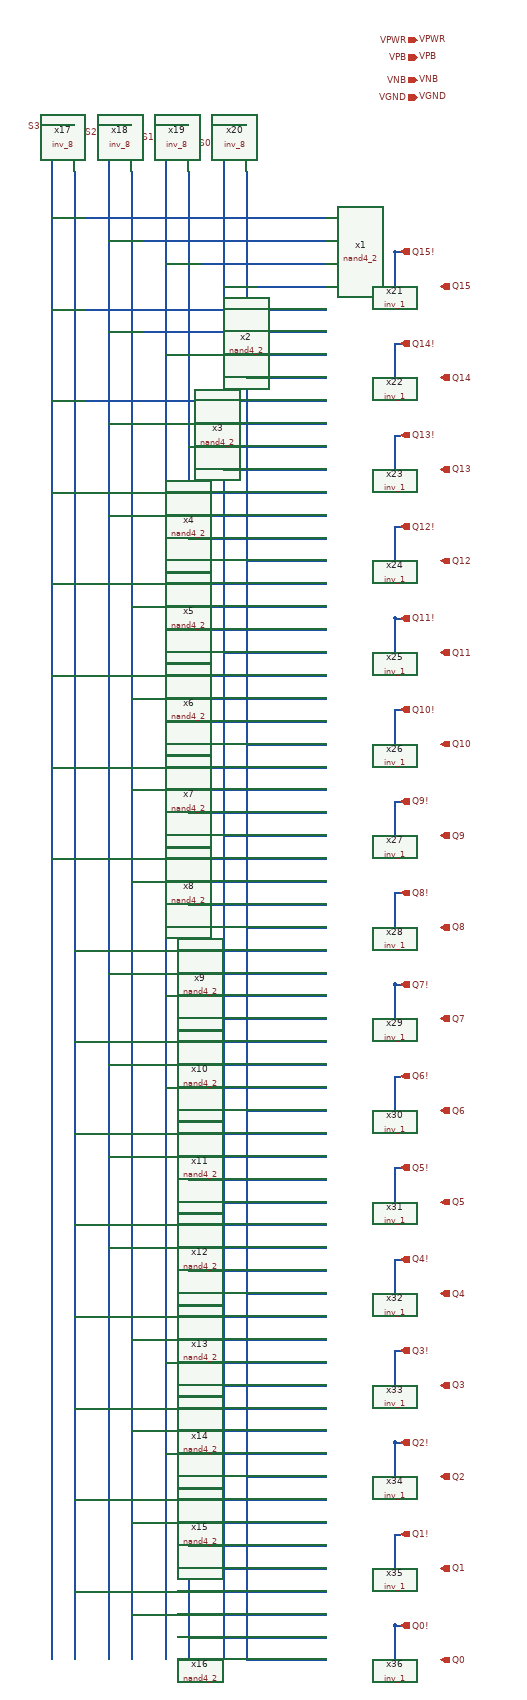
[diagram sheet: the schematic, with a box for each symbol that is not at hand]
v {xschem version=3.1.0 file_version=1.2
}
G {}
K {}
V {}
S {}
E {}
N 700 -2800 740 -2800 {
lab=S0}
N 700 -2800 700 -120 {
lab=S0}
N 600 -2800 600 -120 {
lab=S1}
N 500 -2800 500 -120 {
lab=S2}
N 400 -2800 400 -120 {
lab=S3}
N 600 -2800 640 -2800 {
lab=S1}
N 500 -2800 540 -2800 {
lab=S2}
N 400 -2800 440 -2800 {
lab=S3}
N 740 -2720 740 -120 {
lab=#net1}
N 640 -2720 640 -120 {
lab=#net2}
N 540 -2720 540 -120 {
lab=#net3}
N 440 -2720 440 -120 {
lab=#net4}
N 400 -2640 880 -2640 {
lab=S3}
N 500 -2600 880 -2600 {
lab=S2}
N 600 -2560 880 -2560 {
lab=S1}
N 700 -2520 880 -2520 {
lab=S0}
N 400 -2480 880 -2480 {
lab=S3}
N 400 -2320 880 -2320 {
lab=S3}
N 400 -2160 880 -2160 {
lab=S3}
N 400 -2000 880 -2000 {
lab=S3}
N 400 -1840 880 -1840 {
lab=S3}
N 400 -1680 880 -1680 {
lab=S3}
N 400 -1520 880 -1520 {
lab=S3}
N 500 -2440 880 -2440 {
lab=S2}
N 500 -2280 880 -2280 {
lab=S2}
N 500 -2120 880 -2120 {
lab=S2}
N 540 -1960 880 -1960 {
lab=#net3}
N 540 -1800 880 -1800 {
lab=#net3}
N 540 -1640 880 -1640 {
lab=#net3}
N 540 -1480 880 -1480 {
lab=#net3}
N 440 -1360 880 -1360 {
lab=#net4}
N 440 -1200 880 -1200 {
lab=#net4}
N 440 -1040 880 -1040 {
lab=#net4}
N 440 -880 880 -880 {
lab=#net4}
N 440 -720 880 -720 {
lab=#net4}
N 440 -560 880 -560 {
lab=#net4}
N 440 -400 880 -400 {
lab=#net4}
N 440 -240 880 -240 {
lab=#net4}
N 500 -1320 880 -1320 {
lab=S2}
N 500 -1160 880 -1160 {
lab=S2}
N 500 -1000 880 -1000 {
lab=S2}
N 500 -840 880 -840 {
lab=S2}
N 540 -680 880 -680 {
lab=#net3}
N 540 -520 880 -520 {
lab=#net3}
N 540 -360 880 -360 {
lab=#net3}
N 540 -200 880 -200 {
lab=#net3}
N 740 -2360 880 -2360 {
lab=#net1}
N 700 -2200 880 -2200 {
lab=S0}
N 740 -2040 880 -2040 {
lab=#net1}
N 700 -1880 880 -1880 {
lab=S0}
N 740 -1720 880 -1720 {
lab=#net1}
N 700 -1560 880 -1560 {
lab=S0}
N 740 -1400 880 -1400 {
lab=#net1}
N 700 -1240 880 -1240 {
lab=S0}
N 740 -1080 880 -1080 {
lab=#net1}
N 700 -920 880 -920 {
lab=S0}
N 740 -760 880 -760 {
lab=#net1}
N 700 -600 880 -600 {
lab=S0}
N 740 -440 880 -440 {
lab=#net1}
N 700 -280 880 -280 {
lab=S0}
N 740 -120 880 -120 {
lab=#net1}
N 600 -2400 880 -2400 {
lab=S1}
N 640 -2240 880 -2240 {
lab=#net2}
N 640 -2080 880 -2080 {
lab=#net2}
N 600 -1920 880 -1920 {
lab=S1}
N 600 -1760 880 -1760 {
lab=S1}
N 640 -1600 880 -1600 {
lab=#net2}
N 640 -1440 880 -1440 {
lab=#net2}
N 600 -1120 880 -1120 {
lab=S1}
N 640 -800 880 -800 {
lab=#net2}
N 600 -480 880 -480 {
lab=S1}
N 600 -1280 880 -1280 {
lab=S1}
N 640 -960 880 -960 {
lab=#net2}
N 600 -640 880 -640 {
lab=S1}
N 640 -320 880 -320 {
lab=#net2}
N 640 -160 880 -160 {
lab=#net2}
N 1000 -2580 1010 -2580 {
lab=Q15!}
N 1000 -2420 1010 -2420 {
lab=Q14!}
N 1000 -2580 1010 -2580 {
lab=Q15!}
N 1000 -2260 1010 -2260 {
lab=Q13!}
N 1000 -2100 1010 -2100 {
lab=Q12!}
N 1000 -1940 1010 -1940 {
lab=Q11!}
N 1000 -1780 1010 -1780 {
lab=Q10!}
N 1000 -1940 1010 -1940 {
lab=Q11!}
N 1000 -1620 1010 -1620 {
lab=Q9!}
N 1000 -1460 1010 -1460 {
lab=Q8!}
N 1000 -1300 1010 -1300 {
lab=Q7!}
N 1000 -1140 1010 -1140 {
lab=Q6!}
N 1000 -1300 1010 -1300 {
lab=Q7!}
N 1000 -820 1010 -820 {
lab=Q4!}
N 1000 -660 1010 -660 {
lab=Q3!}
N 1000 -500 1010 -500 {
lab=Q2!}
N 1000 -340 1010 -340 {
lab=Q1!}
N 1000 -500 1010 -500 {
lab=Q2!}
N 1000 -180 1010 -180 {
lab=Q0!}
N 1000 -180 1010 -180 {
lab=Q0!}
N 1000 -980 1010 -980 {
lab=Q5!}
N 1000 -2580 1000 -2520 {
lab=Q15!}
N 1000 -2420 1000 -2360 {
lab=Q14!}
N 1000 -2260 1000 -2200 {
lab=Q13!}
N 1000 -2100 1000 -2040 {
lab=Q12!}
N 1000 -1940 1000 -1880 {
lab=Q11!}
N 1000 -1780 1000 -1720 {
lab=Q10!}
N 1000 -1620 1000 -1560 {
lab=Q9!}
N 1000 -1460 1000 -1400 {
lab=Q8!}
N 1000 -1300 1000 -1240 {
lab=Q7!}
N 1000 -1140 1000 -1080 {
lab=Q6!}
N 1000 -980 1000 -920 {
lab=Q5!}
N 1000 -820 1000 -760 {
lab=Q4!}
N 1000 -660 1000 -600 {
lab=Q3!}
N 1000 -500 1000 -440 {
lab=Q2!}
N 1000 -340 1000 -280 {
lab=Q1!}
N 1000 -180 1000 -120 {
lab=Q0!}
C {devices/ipin.sym} 400 -2800 0 0 {name=p9 lab=S3}
C {devices/ipin.sym} 500 -2790 0 0 {name=p10 lab=S2}
C {devices/ipin.sym} 600 -2780 0 0 {name=p35 lab=S1}
C {devices/ipin.sym} 700 -2770 0 0 {name=p36 lab=S0}
C {devices/ipin.sym} 1040 -2850 0 0 {name=p37 lab=VGND}
C {devices/ipin.sym} 1040 -2950 0 0 {name=p38 lab=VPWR
}
C {devices/ipin.sym} 1040 -2880 0 0 {name=p41 lab=VNB}
C {devices/ipin.sym} 1040 -2920 0 0 {name=p42 lab=VPB

}
C {devices/lab_pin.sym} 1040 -2950 0 1 {name=p39 sig_type=std_logic lab=VPWR
}
C {devices/lab_pin.sym} 1040 -2850 0 1 {name=p40 sig_type=std_logic lab=VGND}
C {devices/lab_pin.sym} 1040 -2920 0 1 {name=p43 sig_type=std_logic lab=VPB}
C {devices/lab_pin.sym} 1040 -2880 0 1 {name=p44 sig_type=std_logic lab=VNB}
C {sky130_stdcells/nand4_2.sym} 940 -2580 0 0 {name=x1 VGND=VGND VNB=VNB VPB=VPB VPWR=VPWR prefix=sky130_fd_sc_hd__ }
C {sky130_stdcells/nand4_2.sym} 940 -2420 0 0 {name=x2 VGND=VGND VNB=VNB VPB=VPB VPWR=VPWR prefix=sky130_fd_sc_hd__ }
C {sky130_stdcells/nand4_2.sym} 940 -2260 0 0 {name=x3 VGND=VGND VNB=VNB VPB=VPB VPWR=VPWR prefix=sky130_fd_sc_hd__ }
C {sky130_stdcells/nand4_2.sym} 940 -2100 0 0 {name=x4 VGND=VGND VNB=VNB VPB=VPB VPWR=VPWR prefix=sky130_fd_sc_hd__ }
C {sky130_stdcells/nand4_2.sym} 940 -1940 0 0 {name=x5 VGND=VGND VNB=VNB VPB=VPB VPWR=VPWR prefix=sky130_fd_sc_hd__ }
C {sky130_stdcells/nand4_2.sym} 940 -1780 0 0 {name=x6 VGND=VGND VNB=VNB VPB=VPB VPWR=VPWR prefix=sky130_fd_sc_hd__ }
C {sky130_stdcells/nand4_2.sym} 940 -1620 0 0 {name=x7 VGND=VGND VNB=VNB VPB=VPB VPWR=VPWR prefix=sky130_fd_sc_hd__ }
C {sky130_stdcells/nand4_2.sym} 940 -1460 0 0 {name=x8 VGND=VGND VNB=VNB VPB=VPB VPWR=VPWR prefix=sky130_fd_sc_hd__ }
C {sky130_stdcells/nand4_2.sym} 940 -1300 0 0 {name=x9 VGND=VGND VNB=VNB VPB=VPB VPWR=VPWR prefix=sky130_fd_sc_hd__ }
C {sky130_stdcells/nand4_2.sym} 940 -1140 0 0 {name=x10 VGND=VGND VNB=VNB VPB=VPB VPWR=VPWR prefix=sky130_fd_sc_hd__ }
C {sky130_stdcells/nand4_2.sym} 940 -980 0 0 {name=x11 VGND=VGND VNB=VNB VPB=VPB VPWR=VPWR prefix=sky130_fd_sc_hd__ }
C {sky130_stdcells/nand4_2.sym} 940 -820 0 0 {name=x12 VGND=VGND VNB=VNB VPB=VPB VPWR=VPWR prefix=sky130_fd_sc_hd__ }
C {sky130_stdcells/nand4_2.sym} 940 -660 0 0 {name=x13 VGND=VGND VNB=VNB VPB=VPB VPWR=VPWR prefix=sky130_fd_sc_hd__ }
C {sky130_stdcells/nand4_2.sym} 940 -500 0 0 {name=x14 VGND=VGND VNB=VNB VPB=VPB VPWR=VPWR prefix=sky130_fd_sc_hd__ }
C {sky130_stdcells/nand4_2.sym} 940 -340 0 0 {name=x15 VGND=VGND VNB=VNB VPB=VPB VPWR=VPWR prefix=sky130_fd_sc_hd__ }
C {sky130_stdcells/nand4_2.sym} 940 -180 0 0 {name=x16 VGND=VGND VNB=VNB VPB=VPB VPWR=VPWR prefix=sky130_fd_sc_hd__ }
C {devices/opin.sym} 1010 -2420 0 0 {name=p1 lab=Q14!
}
C {devices/opin.sym} 1010 -2580 0 0 {name=p3 lab=Q15!}
C {devices/opin.sym} 1010 -2260 0 0 {name=p4 lab=Q13!
}
C {devices/opin.sym} 1010 -2100 0 0 {name=p5 lab=Q12!}
C {devices/opin.sym} 1010 -1780 0 0 {name=p7 lab=Q10!}
C {devices/opin.sym} 1010 -1940 0 0 {name=p8 lab=Q11!}
C {devices/opin.sym} 1010 -1620 0 0 {name=p11 lab=Q9!}
C {devices/opin.sym} 1010 -1460 0 0 {name=p12 lab=Q8!}
C {devices/opin.sym} 1010 -1300 0 0 {name=p13 lab=Q7!}
C {devices/opin.sym} 1010 -1140 0 0 {name=p14 lab=Q6!}
C {devices/opin.sym} 1010 -820 0 0 {name=p16 lab=Q4!
}
C {devices/opin.sym} 1010 -660 0 0 {name=p17 lab=Q3!}
C {devices/opin.sym} 1010 -500 0 0 {name=p18 lab=Q2!}
C {devices/opin.sym} 1010 -340 0 0 {name=p19 lab=Q1!}
C {devices/opin.sym} 1010 -180 0 0 {name=p21 lab=Q0!}
C {devices/opin.sym} 1010 -980 0 0 {name=p2 lab=Q5!
}
C {sky130_stdcells/inv_8.sym} 440 -2760 1 0 {name=x17 VGND=VGND VNB=VNB VPB=VPB VPWR=VPWR prefix=sky130_fd_sc_hd__ }
C {sky130_stdcells/inv_8.sym} 540 -2760 1 0 {name=x18 VGND=VGND VNB=VNB VPB=VPB VPWR=VPWR prefix=sky130_fd_sc_hd__ }
C {sky130_stdcells/inv_8.sym} 640 -2760 1 0 {name=x19 VGND=VGND VNB=VNB VPB=VPB VPWR=VPWR prefix=sky130_fd_sc_hd__ }
C {sky130_stdcells/inv_8.sym} 740 -2760 1 0 {name=x20 VGND=VGND VNB=VNB VPB=VPB VPWR=VPWR prefix=sky130_fd_sc_hd__ }
C {sky130_stdcells/inv_1.sym} 1040 -2520 0 0 {name=x21 VGND=VGND VNB=VNB VPB=VPB VPWR=VPWR prefix=sky130_fd_sc_hd__ }
C {sky130_stdcells/inv_1.sym} 1040 -2360 0 0 {name=x22 VGND=VGND VNB=VNB VPB=VPB VPWR=VPWR prefix=sky130_fd_sc_hd__ }
C {sky130_stdcells/inv_1.sym} 1040 -2200 0 0 {name=x23 VGND=VGND VNB=VNB VPB=VPB VPWR=VPWR prefix=sky130_fd_sc_hd__ }
C {sky130_stdcells/inv_1.sym} 1040 -2040 0 0 {name=x24 VGND=VGND VNB=VNB VPB=VPB VPWR=VPWR prefix=sky130_fd_sc_hd__ }
C {sky130_stdcells/inv_1.sym} 1040 -1880 0 0 {name=x25 VGND=VGND VNB=VNB VPB=VPB VPWR=VPWR prefix=sky130_fd_sc_hd__ }
C {sky130_stdcells/inv_1.sym} 1040 -1720 0 0 {name=x26 VGND=VGND VNB=VNB VPB=VPB VPWR=VPWR prefix=sky130_fd_sc_hd__ }
C {sky130_stdcells/inv_1.sym} 1040 -1560 0 0 {name=x27 VGND=VGND VNB=VNB VPB=VPB VPWR=VPWR prefix=sky130_fd_sc_hd__ }
C {sky130_stdcells/inv_1.sym} 1040 -1400 0 0 {name=x28 VGND=VGND VNB=VNB VPB=VPB VPWR=VPWR prefix=sky130_fd_sc_hd__ }
C {sky130_stdcells/inv_1.sym} 1040 -1240 0 0 {name=x29 VGND=VGND VNB=VNB VPB=VPB VPWR=VPWR prefix=sky130_fd_sc_hd__ }
C {sky130_stdcells/inv_1.sym} 1040 -1080 0 0 {name=x30 VGND=VGND VNB=VNB VPB=VPB VPWR=VPWR prefix=sky130_fd_sc_hd__ }
C {sky130_stdcells/inv_1.sym} 1040 -920 0 0 {name=x31 VGND=VGND VNB=VNB VPB=VPB VPWR=VPWR prefix=sky130_fd_sc_hd__ }
C {sky130_stdcells/inv_1.sym} 1040 -760 0 0 {name=x32 VGND=VGND VNB=VNB VPB=VPB VPWR=VPWR prefix=sky130_fd_sc_hd__ }
C {sky130_stdcells/inv_1.sym} 1040 -600 0 0 {name=x33 VGND=VGND VNB=VNB VPB=VPB VPWR=VPWR prefix=sky130_fd_sc_hd__ }
C {sky130_stdcells/inv_1.sym} 1040 -440 0 0 {name=x34 VGND=VGND VNB=VNB VPB=VPB VPWR=VPWR prefix=sky130_fd_sc_hd__ }
C {sky130_stdcells/inv_1.sym} 1040 -280 0 0 {name=x35 VGND=VGND VNB=VNB VPB=VPB VPWR=VPWR prefix=sky130_fd_sc_hd__ }
C {sky130_stdcells/inv_1.sym} 1040 -120 0 0 {name=x36 VGND=VGND VNB=VNB VPB=VPB VPWR=VPWR prefix=sky130_fd_sc_hd__ }
C {devices/opin.sym} 1080 -2360 0 0 {name=p6 lab=Q14
}
C {devices/opin.sym} 1080 -2520 0 0 {name=p15 lab=Q15}
C {devices/opin.sym} 1080 -2200 0 0 {name=p20 lab=Q13
}
C {devices/opin.sym} 1080 -2040 0 0 {name=p22 lab=Q12}
C {devices/opin.sym} 1080 -1720 0 0 {name=p23 lab=Q10}
C {devices/opin.sym} 1080 -1880 0 0 {name=p24 lab=Q11}
C {devices/opin.sym} 1080 -1560 0 0 {name=p25 lab=Q9}
C {devices/opin.sym} 1080 -1400 0 0 {name=p26 lab=Q8}
C {devices/opin.sym} 1080 -1240 0 0 {name=p27 lab=Q7}
C {devices/opin.sym} 1080 -1080 0 0 {name=p28 lab=Q6}
C {devices/opin.sym} 1080 -760 0 0 {name=p29 lab=Q4
}
C {devices/opin.sym} 1080 -600 0 0 {name=p30 lab=Q3}
C {devices/opin.sym} 1080 -440 0 0 {name=p31 lab=Q2}
C {devices/opin.sym} 1080 -280 0 0 {name=p32 lab=Q1}
C {devices/opin.sym} 1080 -120 0 0 {name=p33 lab=Q0}
C {devices/opin.sym} 1080 -920 0 0 {name=p34 lab=Q5
}
